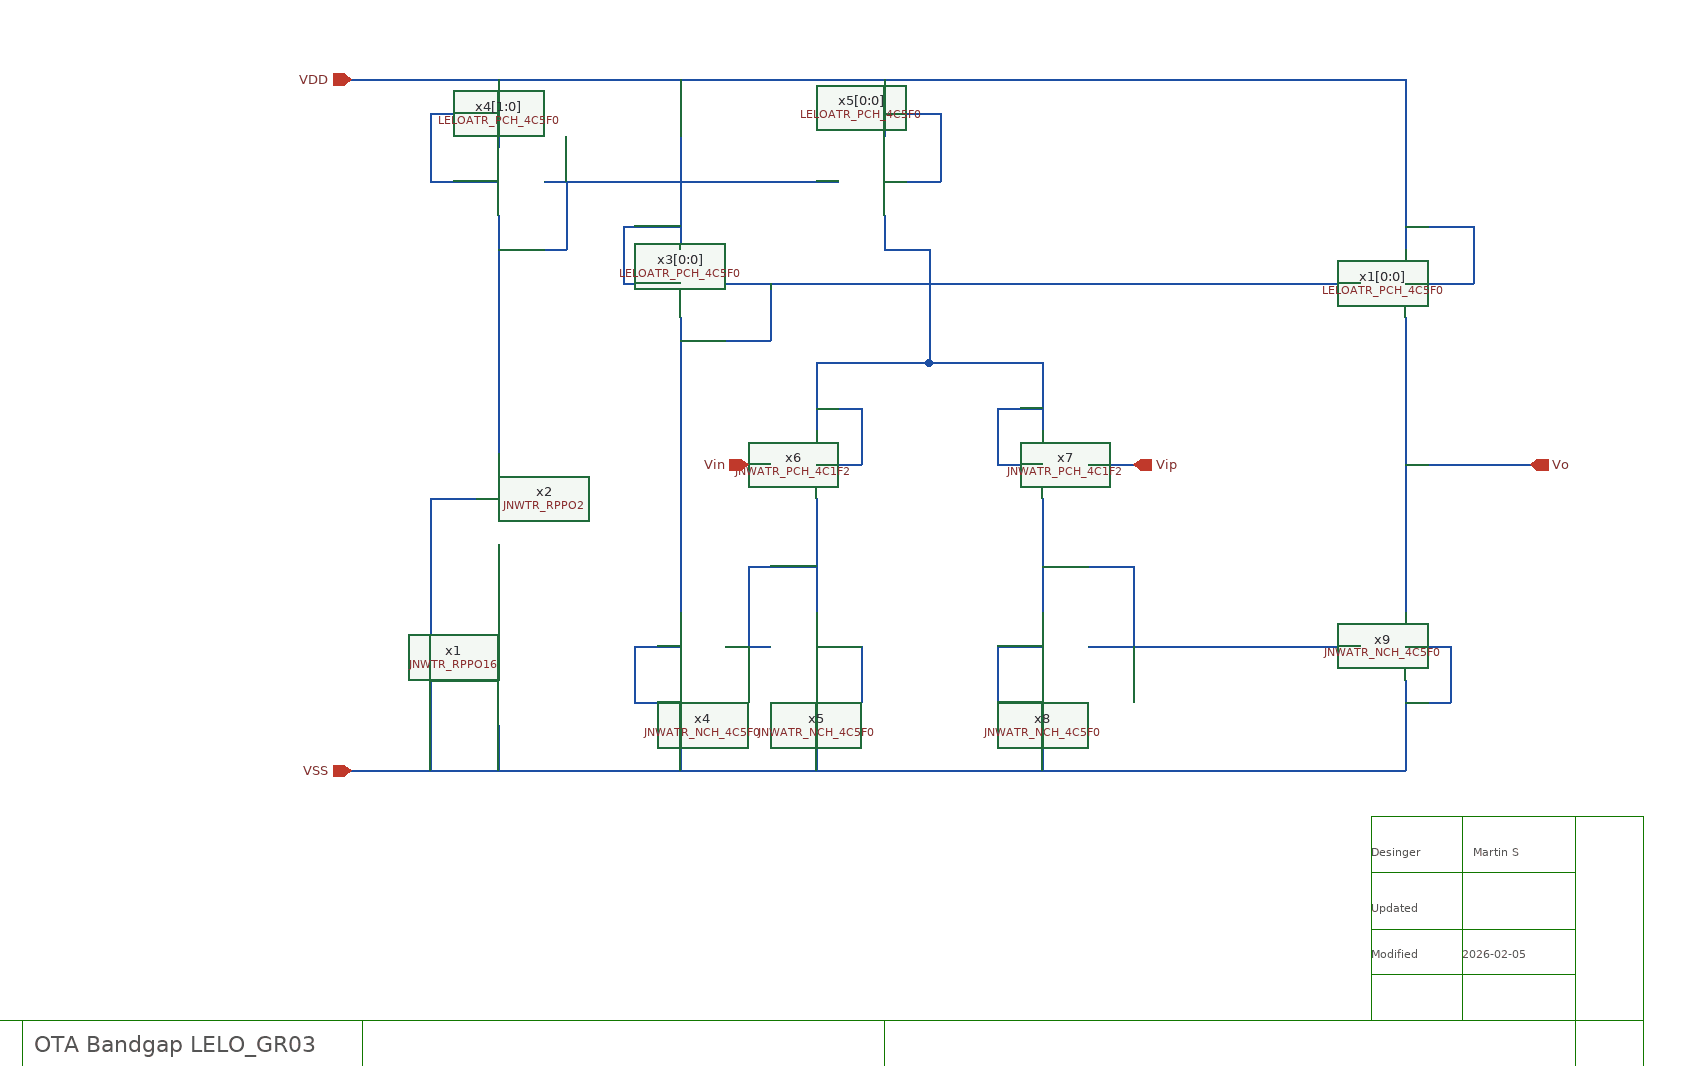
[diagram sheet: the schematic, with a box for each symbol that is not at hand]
v {xschem version=3.4.7 file_version=1.2}
G {}
K {}
V {}
S {}
E {}
L 4 -1020 900 -720 900 {}
L 4 -720 900 -720 950 {}
L 4 -720 900 -260 900 {}
L 4 -260 900 -260 960 {}
L 4 -720 960 -260 960 {}
L 4 -720 950 -720 960 {}
L 4 -1020 960 -720 960 {}
L 4 160 900 350 900 {}
L 4 350 900 350 960 {}
L 4 150 960 350 960 {}
L 4 350 900 410 900 {}
L 4 410 900 410 960 {}
L 4 350 960 410 960 {}
L 4 170 860 350 860 {}
L 4 350 860 350 900 {}
L 4 350 820 350 860 {}
L 4 170 820 350 820 {}
L 4 170 820 170 860 {}
L 4 170 770 170 820 {}
L 4 170 770 350 770 {}
L 4 350 770 350 820 {}
L 4 350 720 350 770 {}
L 4 170 720 350 720 {}
L 4 170 720 170 770 {}
L 4 410 720 410 900 {}
L 4 340 720 410 720 {}
L 4 250 720 250 900 {}
L 4 -260 900 160 900 {}
L 4 -260 960 160 960 {}
L 4 170 860 170 900 {}
L 4 -1020 900 -1020 960 {}
L 4 -1070 960 -1020 960 {}
L 4 -1080 960 -1070 960 {}
L 4 -1080 900 -1080 960 {}
L 4 -1080 900 -1020 900 {}
T {OTA Bandgap     LELO_GR03
} -1010 910 0 0 0.7 0.7 {halign=center
valign=top}
T {Desinger} 170 740 0 0 0.3 0.3 {}
T {Updated} 170 790 0 0 0.3 0.3 {}
T {Modified} 170 830 0 0 0.3 0.3 {}
T {Martin S} 260 740 0 0 0.3 0.3 {}
T {2026-02-05 } 250 830 0 0 0.3 0.3 {}
N -600 70 -600 130 {lab=VDD}
N -560 160 -300 160 {lab=#net1}
N -440 70 -440 220 {lab=VDD}
N -660 160 -600 160 {lab=VDD}
N -660 100 -660 160 {lab=VDD}
N -660 100 -600 100 {lab=VDD}
N -600 190 -600 400 {lab=#net1}
N -600 480 -600 560 {lab=#net2}
N -490 250 -440 250 {lab=VDD}
N -490 200 -490 250 {lab=VDD}
N -490 200 -440 200 {lab=VDD}
N -260 70 -260 120 {lab=VDD}
N -260 160 -210 160 {lab=VDD}
N -210 110 -210 160 {lab=VDD}
N -210 100 -210 110 {lab=VDD}
N -260 100 -210 100 {lab=VDD}
N -600 640 -600 680 {lab=VSS}
N -660 440 -620 440 {lab=VSS}
N -660 440 -660 680 {lab=VSS}
N -660 600 -620 600 {lab=VSS}
N -440 280 -440 540 {lab=#net3}
N -440 600 -440 680 {lab=VSS}
N -480 570 -440 570 {lab=VSS}
N -480 570 -480 620 {lab=VSS}
N -480 620 -440 620 {lab=VSS}
N -400 570 -360 570 {lab=#net4}
N -320 600 -320 680 {lab=VSS}
N -320 570 -280 570 {lab=VSS}
N -280 570 -280 620 {lab=VSS}
N -320 620 -280 620 {lab=VSS}
N -320 440 -320 540 {lab=#net4}
N -380 500 -380 570 {lab=#net4}
N -380 500 -320 500 {lab=#net4}
N -80 410 -40 410 {lab=Vip}
N -260 190 -260 220 {lab=#net5}
N -260 220 -220 220 {lab=#net5}
N -220 220 -220 320 {lab=#net5}
N -320 320 -220 320 {lab=#net5}
N -320 320 -320 380 {lab=#net5}
N -320 410 -280 410 {lab=#net5}
N -280 360 -280 410 {lab=#net5}
N -320 360 -280 360 {lab=#net5}
N -220 320 -120 320 {lab=#net5}
N -120 320 -120 380 {lab=#net5}
N -160 410 -120 410 {lab=#net5}
N -160 360 -160 410 {lab=#net5}
N -160 360 -120 360 {lab=#net5}
N -120 440 -120 540 {lab=#net6}
N -120 600 -120 680 {lab=VSS}
N -160 570 -120 570 {lab=VSS}
N -160 570 -160 620 {lab=VSS}
N -160 620 -120 620 {lab=VSS}
N -80 570 160 570 {lab=#net6}
N -120 500 -40 500 {lab=#net6}
N -40 500 -40 570 {lab=#net6}
N 200 600 200 680 {lab=VSS}
N 200 570 240 570 {lab=VSS}
N 240 570 240 620 {lab=VSS}
N 200 620 240 620 {lab=VSS}
N -730 680 200 680 {lab=VSS}
N -400 250 160 250 {lab=#net3}
N 200 280 200 540 {lab=Vo}
N 200 410 310 410 {lab=Vo}
N 200 70 200 220 {lab=VDD}
N -730 70 200 70 {lab=VDD}
N 200 250 260 250 {lab=VDD}
N 260 200 260 250 {lab=VDD}
N 200 200 260 200 {lab=VDD}
N -360 250 -360 300 {lab=#net3}
N -440 300 -360 300 {lab=#net3}
N -540 160 -540 220 {lab=#net1}
N -600 220 -540 220 {lab=#net1}
N -380 410 -360 410 {lab=Vin}
C {/home/marti/pro/aicex/ip/lelo_gr03_sky130a/design/LELO_ATR_SKY130A/LELOATR_PCH_4C5F0.sym} -560 160 0 1 {name=x4[1:0]}
C {/home/marti/pro/aicex/ip/lelo_gr03_sky130a/design/LELO_ATR_SKY130A/LELOATR_PCH_4C5F0.sym} -400 250 0 1 {name=x3[0:0]}
C {/home/marti/pro/aicex/ip/lelo_gr03_sky130a/design/JNW_TR_SKY130A/JNWTR_RPPO16.sym} -600 560 1 0 {name=x1 }
C {/home/marti/pro/aicex/ip/lelo_gr03_sky130a/design/JNW_TR_SKY130A/JNWTR_RPPO2.sym} -600 400 1 0 {name=x2 }
C {/home/marti/pro/aicex/ip/lelo_gr03_sky130a/design/LELO_ATR_SKY130A/LELOATR_PCH_4C5F0.sym} -300 160 0 0 {name=x5[0:0]}
C {/home/marti/pro/aicex/ip/lelo_gr03_sky130a/design/JNW_ATR_SKY130A/JNWATR_NCH_4C5F0.sym} -400 570 0 1 {name=x4 }
C {/home/marti/pro/aicex/ip/lelo_gr03_sky130a/design/JNW_ATR_SKY130A/JNWATR_NCH_4C5F0.sym} -360 570 0 0 {name=x5 }
C {/home/marti/pro/aicex/ip/lelo_gr03_sky130a/design/JNW_ATR_SKY130A/JNWATR_PCH_4C1F2.sym} -360 410 0 0 {name=x6 }
C {/home/marti/pro/aicex/ip/lelo_gr03_sky130a/design/JNW_ATR_SKY130A/JNWATR_PCH_4C1F2.sym} -80 410 0 1 {name=x7 }
C {/home/marti/pro/aicex/ip/lelo_gr03_sky130a/design/JNW_ATR_SKY130A/JNWATR_NCH_4C5F0.sym} -80 570 0 1 {name=x8 }
C {/home/marti/pro/aicex/ip/lelo_gr03_sky130a/design/JNW_ATR_SKY130A/JNWATR_NCH_4C5F0.sym} 160 570 0 0 {name=x9 }
C {/home/marti/pro/aicex/ip/lelo_gr03_sky130a/design/LELO_ATR_SKY130A/LELOATR_PCH_4C5F0.sym} 160 250 0 0 {name=x1[0:0]}
C {ipin.sym} -730 70 0 0 {name=p1 lab=VDD}
C {ipin.sym} -730 680 0 0 {name=p2 lab=VSS
}
C {ipin.sym} -380 410 0 0 {name=p3 lab=Vin
}
C {ipin.sym} -40 410 0 1 {name=p4 lab=Vip}
C {opin.sym} 310 410 0 0 {name=p5 lab=Vo}
